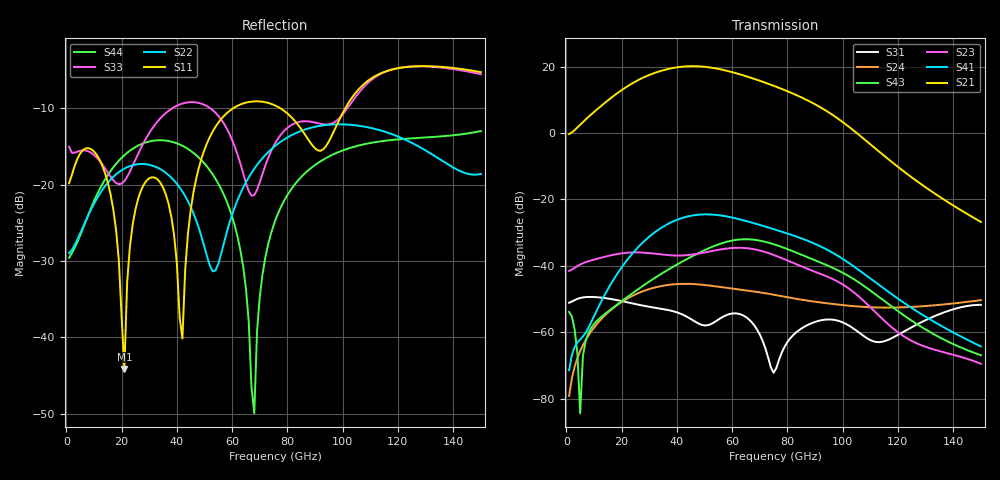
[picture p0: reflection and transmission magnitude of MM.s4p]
! File created by SignalIntegrity v1.4.3: Signal and Power Integrity Tools
! https://github.com/Nubis-Communications/SignalIntegrity
# MHz S MA R 50.0
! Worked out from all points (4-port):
!   150 points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, 1 GHz to 150 GHz, reference 50 ohm
!   strongest paths, dB at 1 GHz, 38 GHz, 76 GHz, 113 GHz, 150 GHz:
!     S21: -0.3, 19.5, 13.9, -5.5, -26.8
!     S41: -71.5, -26.9, -29.2, -45.7, -64.3
!     S23: -41.5, -36.8, -37.0, -54.9, -69.5
!     S43: -53.9, -40.6, -33.7, -49.3, -66.9
!     S24: -79.2, -45.6, -48.8, -52.6, -50.3
!     S31: -51.1, -53.5, -70.7, -63.0, -51.7
!   lowest |S11| = -44.2 dB at 21 GHz (marker M1), VSWR 1.01, Z = 49.8 - j0.584 ohm
!   |S11| at or under -10 dB: start of sweep to 60.39 GHz; 77.4 GHz to 100.9 GHz (23.54 GHz wide, 26.4 % of centre)
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1000  0.1021 -33.1  1.157e-10 65.3  0.002776 -176.4  2.945e-08 87.7
      0.9654 3.9  0.03551 -170.2  0.008369 -177.7  0.0001097 -76.0
      0.002776 -176.4  3.763e-08 72.5  0.1769 -50.4  9.595e-06 95.0
      0.0002674 -103.5  7.146e-05 -78.6  0.002018 -172.5  0.03318 -167.1
21000  0.006199 -109.0  7.958e-10 -148.1  0.002813 50.4  3.86e-07 -173.0
       4.739 -81.2  0.1273 -148.7  0.01562 11.2  0.003028 -121.9
       0.002888 53.6  2.931e-07 37.6  0.1056 45.8  0.0001336 14.1
       0.01081 -169.5  0.0009682 -129.8  0.003145 122.2  0.1558 -139.4
42000  0.009803 27.5  9.811e-09 179.9  0.001556 -68.2  4.254e-07 41.1
       10.02 89.3  0.08996 175.4  0.01433 173.8  0.005355 171.6
       0.001847 -77.7  3.421e-07 53.7  0.3395 -103.1  0.000177 -28.8
       0.05283 -13.6  0.001234 -154.5  0.01163 -28.8  0.1795 174.8
50000  0.1697 -51.4  2.783e-08 115.1  0.001423 -93.2  4.018e-07 18.4
       9.975 11.0  0.0388 -174.8  0.01589 101.3  0.005151 148.1
       0.001265 -95.5  6.481e-07 85.8  0.3327 -134.3  0.0002179 -58.8
       0.05963 -97.7  0.001242 -159.4  0.01722 -98.5  0.1372 157.2
59000  0.3035 -87.2  6.156e-08 42.3  0.001367 -116.6  6.774e-07 -8.2
       8.497 -75.5  0.05582 -85.4  0.01841 9.4  0.004597 126.2
       0.001876 -115.7  2.041e-06 55.2  0.2153 -162.8  0.0001772 -126.5
       0.05453 171.7  0.001247 -163.7  0.02357 172.5  0.06962 138.4
78000  0.3114 -135.7  1.708e-07 -105.4  0.0008308 -133.2  6.174e-07 -56.3
       4.62 109.6  0.1933 -98.5  0.01303 167.1  0.003488 81.0
       0.0004992 -95.3  2.414e-06 -83.4  0.2166 -99.5  0.0003769 -57.8
       0.03265 -1.3  0.001165 -176.4  0.01921 -22.7  0.07355 -73.6
150000  0.5447 -167.2  1.372e-07 -131.4  0.002593 -171.6  3.002e-06 -11.7
        0.04584 -55.2  0.1174 -104.2  0.0003342 15.1  0.00304 -74.5
        0.002586 -171.5  1.833e-06 170.5  0.5284 -168.0  9.04e-05 -128.3
        0.0006103 -147.9  0.001621 -80.6  0.0004502 -118.3  0.2241 -95.6
